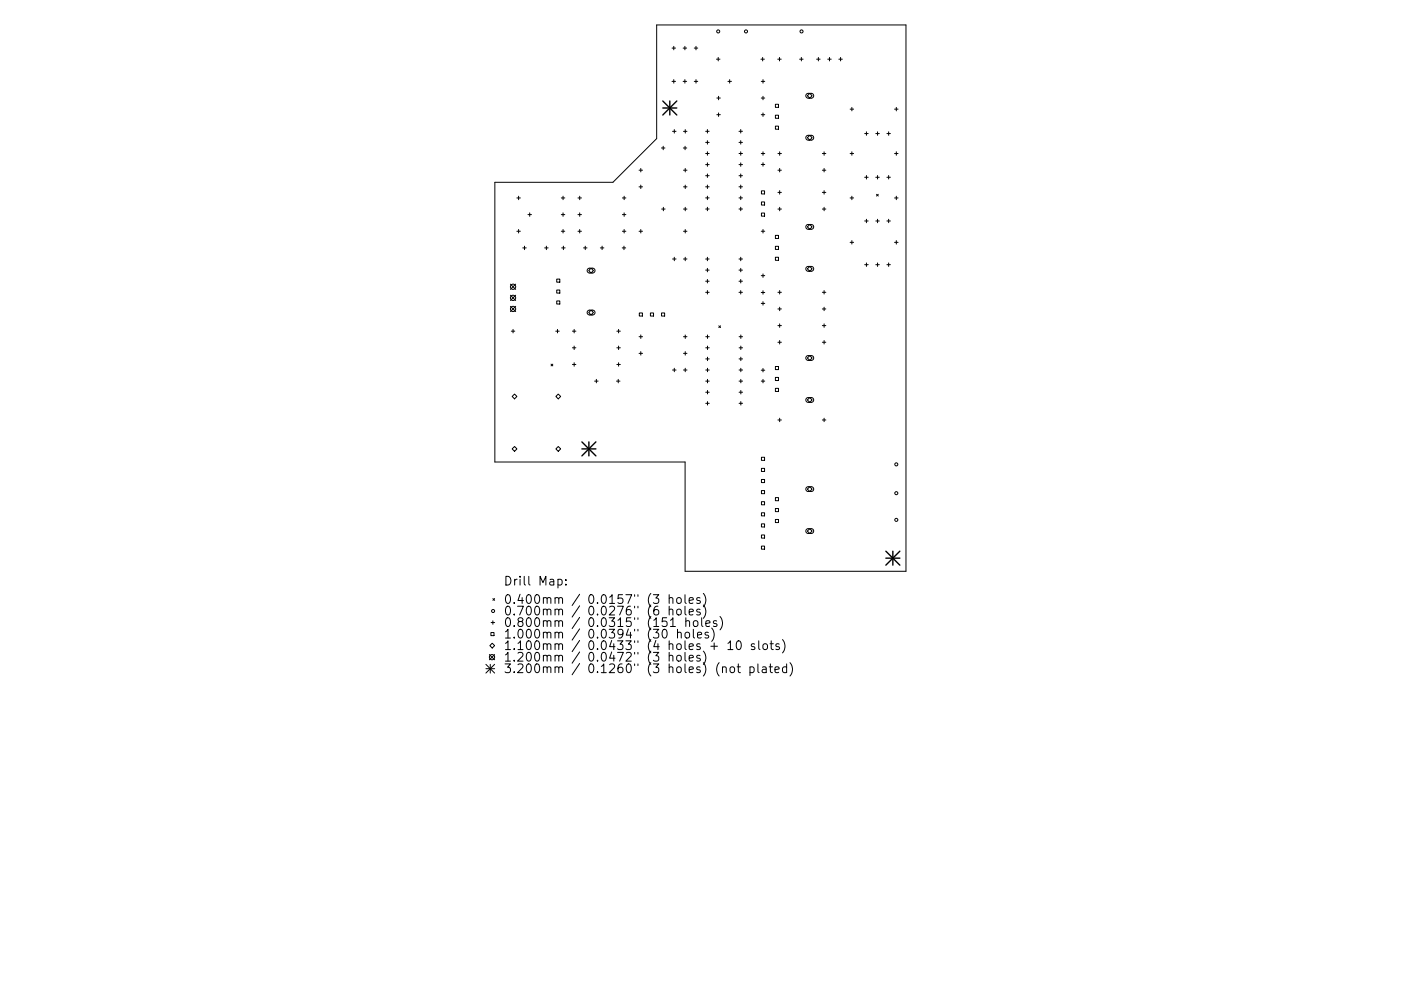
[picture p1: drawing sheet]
<svg xmlns="http://www.w3.org/2000/svg" width="297mm" height="210mm" viewBox="0 0 297 210" stroke-linecap="round" stroke-linejoin="round" font-family="sans-serif">
<defs><g id="words">
<g font-size="2.6">
<text x="106.7" y="124.2">Drill Map:</text>
<text x="106.7" y="128.1">0.400mm / 0.0157&quot; (3 holes)</text>
<text x="106.7" y="130.6">0.700mm / 0.0276&quot; (6 holes)</text>
<text x="106.7" y="133">0.800mm / 0.0315&quot; (151 holes)</text>
<text x="106.7" y="135.5">1.000mm / 0.0394&quot; (30 holes)</text>
<text x="106.7" y="137.9">1.100mm / 0.0433&quot; (4 holes + 10 slots)</text>
<text x="106.7" y="140.4">1.200mm / 0.0472&quot; (3 holes)</text>
<text x="106.7" y="142.8">3.200mm / 0.1260&quot; (3 holes) (not plated)</text>
</g>
</g></defs>
<g fill="none" stroke="#000" stroke-width=".21">
<path d="M142.5 10.2h.7M142.5 17.3h.7M142.9 9.8v.8M142.9 16.9v.7M144.8 10.2h.8M144.8 17.3h.8M145.2 9.8v.8M145.2 16.9v.7M147.2 10.2h.7M147.2 17.3h.7M147.6 9.8v.8M147.6 16.9v.7"/>
<path d="M151.9 12.6h.7M152.3 12.2v.7M154.3 17.3h.8M154.7 16.9v.7M161.3 12.6h.8M161.4 17.3h.7M161.7 12.2v.7M161.8 16.9v.7M164.9 12.6h.7M165.3 12.2v.7M169.5 12.6h.8M169.9 12.2v.7"/>
<path d="M171 20l.3-.2h.9l.3 .3v.4l-.4 .3h-.9l-.3-.4zM171.7 19.8l.5 .5-.5 .5-.5-.5zM173.1 12.6h.8M173.5 12.2v.7M175.5 12.6h.7M175.9 12.2v.7M177.8 12.6h.8M178.2 12.2v.7M104.9 38.7h25.1l9.2-9.3v-24.1h52.9v115.9h-46.8v-23.2h-40.4zM135.5 36.1h.7M135.5 39.6h.7M135.9 35.7v.8"/>
<path d="M135.9 39.3v.7M140.2 31.4h.8M140.6 31v.8M142.6 27.9h.7M143 27.5v.7M144.9 31.4h.7M144.9 36.1h.8M144.9 39.6h.8M144.9 27.9h.8M145.2 31v.8M145.3 27.5v.7M145.3 35.7v.8"/>
<path d="M145.3 39.3v.7M149.6 39.6h.8M149.6 27.9h.8M149.6 30.2h.8M149.6 32.6h.8M149.6 34.9h.8M149.6 37.3h.8M150 27.5v.7M150 29.8v.8M150 32.2v.7M150 34.6v.7M150 36.9v.7"/>
<path d="M150 39.3v.7M152 20.8h.7M152 24.3h.7M152.3 20.4v.8M152.3 24v.7M156.7 39.6h.7M156.7 27.9h.7M156.7 30.2h.7M156.7 32.6h.7M156.7 34.9h.7M156.7 37.3h.7M157.1 27.5v.7"/>
<path d="M157.1 29.8v.8M157.1 32.2v.7M157.1 34.6v.7M157.1 36.9v.7M157.1 39.3v.7M161.4 20.8h.7M161.4 24.3h.7M161.4 32.6h.7M161.4 34.9h.7M161.8 20.4v.8M161.8 24v.7M161.8 32.2v.7"/>
<path d="M161.8 34.5v.8M164.4 22.1h.7v.7h-.7zM164.4 24.4h.7v.7h-.7zM164.4 26.8h.7v.6h-.7zM164.9 36.1h.8M164.9 32.6h.8M165.3 32.2v.7M165.3 35.7v.8M171 28.9l.3-.2h.9l.3 .3v.4l-.4 .3h-.9l-.3-.4zM171.2 29.2l.5-.5 .5 .5-.5 .5zM174.4 36.1h.7M174.4 32.6h.7"/>
<path d="M174.7 32.2v.7M174.7 35.7v.8M180.2 32.6h.8M180.2 23.2h.8M180.6 22.8v.7M180.6 32.2v.7M183.3 28.3h.8M183.3 37.6h.8M183.7 28v.7M183.7 37.2v.8M185.7 28.3h.7M185.7 37.6h.7"/>
<path d="M186.1 28v.7M186.1 37.2v.8M188 28.3h.8M188 37.6h.8M188.4 28v.7M188.4 37.2v.8M189.7 32.6h.7M189.7 23.2h.7M190 22.8v.7M190 32.2v.7M109.6 42h.7M109.6 49.1h.7"/>
<path d="M110 41.6v.8M110 48.7v.7M110.8 52.6h.8M111.2 52.2v.8M111.9 45.5h.8M112.3 45.2v.7M115.5 52.6h.7M115.8 52.2v.8M118 59.2h.7v.7h-.7zM119 42h.7M119 49.1h.7M119 45.5h.7"/>
<path d="M119.1 52.6h.7M119.4 41.6v.8M119.4 45.2v.7M119.4 48.7v.7M119.4 52.2v.8M122.5 42h.8M122.5 49.1h.8M122.5 45.5h.8M122.9 41.6v.8M122.9 45.2v.7M122.9 48.7v.7M123.7 52.6h.8"/>
<path d="M124.1 52.2v.8M124.6 57l.4-.1h.8l.3 .3v.4l-.3 .3h-1l-.3-.4zM124.8 57.4l.5-.5 .5 .5-.5 .5zM127.3 52.6h.7M127.7 52.2v.8M131.9 52.6h.8M132 42h.7M132 49.1h.7M132 45.5h.7M132.3 52.2v.8M132.3 41.6v.8M132.3 45.2v.7"/>
<path d="M132.3 48.7v.7M135.5 49.1h.7M135.9 48.7v.7M140.3 44.4h.7M140.6 44v.7M142.6 55h.7M143 54.6v.7M144.9 49.1h.8M144.9 44.4h.8M144.9 55h.8M145.3 44v.7M145.3 48.7v.7"/>
<path d="M145.3 54.6v.7M149.6 42h.8M149.6 44.3h.8M149.6 55h.8M149.6 57.3h.8M149.6 59.7h.8M150 41.6v.8M150 44v.7M150 54.6v.7M150 56.9v.8M150 59.3v.7M156.7 42h.7"/>
<path d="M156.7 44.3h.7M156.7 55h.7M156.7 57.3h.7M156.7 59.7h.7M157.1 41.6v.8M157.1 44v.7M157.1 54.6v.7M157.1 56.9v.8M157.1 59.3v.7M161.4 49.1h.7M161.4 58.5h.7M161.4 40.5h.7v.6h-.7z"/>
<path d="M161.4 42.8h.7v.7h-.7zM161.4 45.2h.7v.7h-.7zM161.8 48.7v.7M161.8 58.1v.8M164.4 49.9h.7v.7h-.7zM164.4 52.3h.7v.6h-.7zM164.4 54.6h.7v.6h-.7zM164.9 44.4h.8M164.9 40.8h.8M165.3 40.4v.8M165.3 44v.7M171 47.8l.3-.2 .9 .1 .3 .2v.4l-.4 .3h-.9l-.3-.4z"/>
<path d="M171 56.7l.3-.2 .9 .1 .3 .2v.4l-.4 .3h-.9l-.3-.4zM171.2 48.1l.5-.5 .5 .5-.5 .5zM171.7 56.5l.5 .5-.5 .5-.5-.5zM174.4 44.4h.7M174.4 40.8h.7M174.7 40.4v.8M174.7 44v.7M180.2 42h.8M180.2 51.4h.8M180.6 41.6v.8M180.6 51v.8M183.3 46.9h.8"/>
<path d="M183.3 56.2h.8M183.7 46.5v.8M183.7 55.8v.7M185.7 46.9h.7M185.7 56.2h.7M185.8 41.2l.4 .4M186.1 46.5v.8M186.1 55.8v.7M186.2 41.2l-.4 .4M188 46.9h.8M188 56.2h.8M188.4 46.5v.8"/>
<path d="M188.4 55.8v.7M189.7 42h.7M189.7 51.4h.7M190 41.6v.8M190 51v.8M108.2 60.3l1.1 1.1M108.2 62.6l1.1 1.2M108.2 65l1.1 1.1M108.4 70.3h.7M108.8 69.9v.7M109.3 60.3l-1.1 1.1M109.3 62.6l-1.1 1.2"/>
<path d="M109.3 65l-1.1 1.1M116.8 77.3l.4 .3M117.2 77.3l-.4 .3M117.8 70.3h.8M118 61.5h.7v.7h-.7zM118 63.8h.7v.7h-.7zM118.2 69.9v.7M121.4 70.3h.7M121.4 73.8h.7M121.4 77.3h.7M121.7 69.9v.7M121.7 73.4v.8"/>
<path d="M121.7 77v.7M124.6 65.9l.4-.1h.8l.3 .3v.4l-.3 .3h-1l-.3-.4zM124.8 66.3l.5-.5 .5 .5-.5 .5zM130.8 70.3h.7M130.8 73.8h.7M130.8 77.3h.7M131.2 69.9v.7M131.2 73.4v.8M131.2 77v.7M135.5 71.4h.7M135.5 75h.7M135.5 66.4h.7v.7h-.7z"/>
<path d="M135.9 71.1v.7M135.9 74.6v.7M137.9 66.4h.7v.7h-.7zM140.3 66.4h.6v.7h-.6zM142.6 78.5h.7M143 78.1v.8M144.9 71.4h.8M144.9 75h.8M144.9 78.5h.8M145.3 71.1v.7M145.3 74.6v.7M145.3 78.1v.8"/>
<path d="M149.6 62h.8M149.6 73.8h.8M149.6 71.4h.8M149.6 78.5h.8M149.6 76.1h.8M150 61.6v.8M150 71.1v.7M150 73.4v.8M150 75.8v.7M150 78.1v.8M152.4 69.1l.4 .4M152.8 69.1l-.4 .4"/>
<path d="M156.7 62h.7M156.7 73.8h.7M156.7 71.4h.7M156.7 78.5h.7M156.7 76.1h.7M157.1 61.6v.8M157.1 71.1v.7M157.1 73.4v.8M157.1 75.8v.7M157.1 78.1v.8M161.4 62.1h.7M161.4 64.4h.7"/>
<path d="M161.4 78.5h.7M161.8 61.7v.7M161.8 64v.7M161.8 78.2v.7M164.4 77.8h.7v.6h-.7zM164.9 62h.8M164.9 65.6h.8M164.9 69.1h.8M164.9 72.6h.8M165.3 61.6v.8M165.3 65.2v.7M165.3 68.7v.8"/>
<path d="M165.3 72.2v.8M171 75.6l.3-.2 .9 .1 .3 .2v.4l-.4 .3h-.9l-.3-.4zM171.7 75.4l.5 .6-.5 .5-.5-.5zM174.4 62h.7M174.4 65.6h.7M174.4 69.1h.7M174.4 72.6h.7M174.7 61.6v.8M174.7 65.2v.7M174.7 68.7v.8M174.7 72.2v.8M108.6 84.1l.5-.5 .5 .5-.5 .5z"/>
<path d="M108.6 95.2l.5-.5 .5 .5-.5 .6zM117.9 84.1l.5-.5 .5 .5-.5 .5zM117.9 95.2l.5-.5 .5 .5-.5 .6zM126.1 80.9h.7M126.4 80.5v.7M130.7 80.9h.7M131.1 80.5v.7M149.6 80.9h.8M149.6 83.2h.8M149.6 85.6h.8M150 80.5v.7M150 82.8v.8"/>
<path d="M150 85.2v.7M156.7 80.9h.7M156.7 83.2h.7M156.7 85.6h.7M157.1 80.5v.7M157.1 82.8v.8M157.1 85.2v.7M161.4 80.9h.7M161.4 97h.7v.7h-.7zM161.4 99.4h.7v.6h-.7zM161.8 80.5v.7M164.4 80.1h.7v.6h-.7z"/>
<path d="M164.4 82.4h.7v.7h-.7zM164.9 89.1h.8M165.3 88.7v.8M171 84.5l.3-.2 .9 .1 .3 .2v.4l-.4 .3h-.9l-.3-.4zM171.7 84.3l.5 .6-.5 .5-.5-.5zM174.4 89.1h.7M174.7 88.7v.8M161.4 101.7h.7v.7h-.7zM161.4 104.1h.7v.6h-.7zM161.4 106.4h.7v.7h-.7zM161.4 108.8h.7v.7h-.7zM161.4 111.2h.7v.6h-.7z"/>
<path d="M161.4 113.5h.7v.7h-.7zM161.4 115.9h.7v.6h-.7zM164.4 105.6h.7v.6h-.7zM164.4 107.9h.7v.7h-.7zM164.4 110.2h.7v.7h-.7zM171 103.4l.3-.1h.9l.3 .3v.3l-.4 .4h-.9l-.3-.4zM171 112.3l.3-.1h.9l.3 .3v.3l-.4 .4h-.9l-.3-.4zM171.2 112.7l.5-.5 .5 .5-.5 .5zM171.7 103.3l.5 .5-.5 .5-.5-.5zM103.8 138.9l1.1 1.1M103.9 137l.5-.5 .5 .5-.5 .5zM104.1 134.2h.6v.7h-.6z"/>
<path d="M104.1 132.1h.8M104.5 127l.4 .4M104.5 131.7v.8M104.9 127l-.4 .4M104.9 138.9l-1.1 1.1M118.3 123l.5-.1 .4 .3v.6l-.2 .2h-.7M120 124v.1M120 123v.2M140.6 133.7l.2-.2a1 1 0 0 1 .5 1.7l-.3 .2a1 1 0 0 1-.4-1.7zM141.9 127l.2-.2 .5 .1 .1 1.1M141.9 129.4l.2-.2 .5 .1 .1 1.2M141.9 139.2l.2-.2 .5 .1 .1 1.2"/>
<path d="M141.9 126.2v1.8M141.9 128.6v1.9M141.9 138.4v1.9M142.1 132.9h1.1M143.6 127l.2-.2 .6 .2v.7l-.1 .2-.5 .1-.2-.2zM143.6 129.4l.2-.2 .6 .2v.7l-.1 .3-.5 .1-.2-.2zM143.6 139.2l.2-.2 .6 .2v.7l-.1 .3-.5 .1-.2-.2zM143.6 134.3l.3-.2 .5 .1v1.2M143.6 133.5v1.9M145.2 126.2v1.6l.3 .2M145.2 128.6v1.6l.3 .3M145.2 138.4v1.6l.3 .3"/>
<path d="M145.3 134.3l.3-.2 .5 .2 .1 .7-.2 .3-.4 .1-.3-.2zM145.4 131.9l.3-.2 .4 .1 .1 1.1M145.4 131.1v1.8M146.1 127.4l.9-.2-.1-.3-.5-.1-.3 .3 .1 .8h.7M146.1 129.9l.9-.2-.1-.4-.5-.1-.3 .3 .1 .9h.7M146.1 139.6l.9-.1-.1-.4-.5-.1-.3 .3 .1 .9h.7M147 133.5v1.6l.3 .3M147.2 131.8l.4-.1 .4 .3v.6l-.4 .3-.4-.1-.2-.2v-.6zM147.9 134.8l.9-.2-.1-.4-.6-.1-.2 .3 .1 .9h.7M148.4 126.9l-.4-.1-.3 .3 .1 .2 .6 .2v.4h-.7M148.4 129.3l-.4-.1-.3 .3 .1 .3 .6 .1v.5h-.7M148.4 139.1l-.4-.1-.3 .3 .1 .3 .6 .1v.5h-.7"/>
<path d="M148.8 131.1v1.6l.2 .2M149.1 125.9a2.13 2.13 0 0 1 0 2.8M149.1 128.4a2.13 2.13 0 0 1 0 2.8M149.1 138.1a2.13 2.13 0 0 1 0 2.9M149.7 132.3l.8-.2-.1-.3-.5-.1-.2 .3v.8h.7M150.2 134.2l-.5-.1-.2 .3 .1 .3 .6 .1v.5h-.7M150.7 137.1h1.4M150.9 133.3a2.13 2.13 0 0 1 0 2.8M151.9 131.8l-.4-.1-.3 .3 .1 .2 .6 .2v.4h-.7M152.7 130.8a2.13 2.13 0 0 1 0 2.8M154.3 136.5l.6-.5v1.8M154.3 137.8h1.1"/>
<path d="M156.3 136.1l.2-.1a1 1 0 0 1 .5 1.6l-.3 .2a1 1 0 0 1-.4-1.7zM160 136.7l-.5-.1-.2 .2 .1 .3 .6 .2v.4h-.7M160.9 136v1.6l.2 .2M161.9 136.7l.5-.1 .3 .3v.6l-.3 .3-.5-.1-.2-.2v-.6zM163.3 136.6h.7M163.5 136v1.6l.5 .2M165.2 136.7l-.4-.1-.3 .2 .1 .3 .6 .2v.4h-.7M165.9 135.7a2.13 2.13 0 0 1 0 2.8M103 140.9l1.9 1.9M103 141.9h1.9M103.9 140.9v1.9M104.9 140.9l-1.9 1.9"/>
<path d="M153.2 141.7l.2-.2 .5 .1 .1 1.1M154.9 141.7l.2-.2 .6 .2v.7l-.1 .2-.5 .1-.2-.2zM156.3 141.5h.7M156.5 140.9v1.5l.5 .3M159 141.6l.5-.1 .4 .3v.6l-.2 .2h-.7M159 141.5v1.8M160.7 140.9v1.5l.3 .3M161.7 141.6h.7l.1 1.1M162.5 141.9l-.7 .1a.36 .36 0 0 0-.2 .4 .36 .36 0 0 0 .2 .3l.7-.1M163.1 141.5h.7M163.3 140.9v1.5l.5 .3M164.3 142.1l.9-.2-.1-.3-.5-.1-.3 .2 .1 .9h.7"/>
<path d="M166.8 141.6l-.5-.1-.4 .3v.6l.2 .2h.7M166.8 140.9v1.8M167.5 140.6a2.13 2.13 0 0 1 0 2.8"/>
<circle cx="152.3" cy="6.7" r=".32"/>
<circle cx="158.2" cy="6.7" r=".32"/>
<circle cx="169.9" cy="6.7" r=".32"/>
<circle cx="108.8" cy="65.6" r=".56"/>
<circle cx="108.8" cy="60.8" r=".56"/>
<circle cx="108.8" cy="63.2" r=".56"/>
<circle cx="190" cy="98.5" r=".32"/>
<circle cx="190" cy="110.3" r=".32"/>
<circle cx="190" cy="104.6" r=".32"/>
<circle cx="104.3" cy="139.4" r=".56"/>
<circle cx="104.5" cy="129.6" r=".32"/>
</g>
<path d="M140.5 21.4l3 3M140.5 22.9h3M142 21.4v3M143.5 21.4l-3 3M123.4 93.8l2.9 2.9M123.4 95.2h2.9M124.9 93.8v2.9M126.3 93.8l-2.9 2.9M187.8 116.9l3 3M187.8 118.4h3M189.3 116.9v3M190.8 116.9l-3 3" fill="none" stroke="#000" stroke-width=".3"/>
<use href="#words"/>
</svg>
